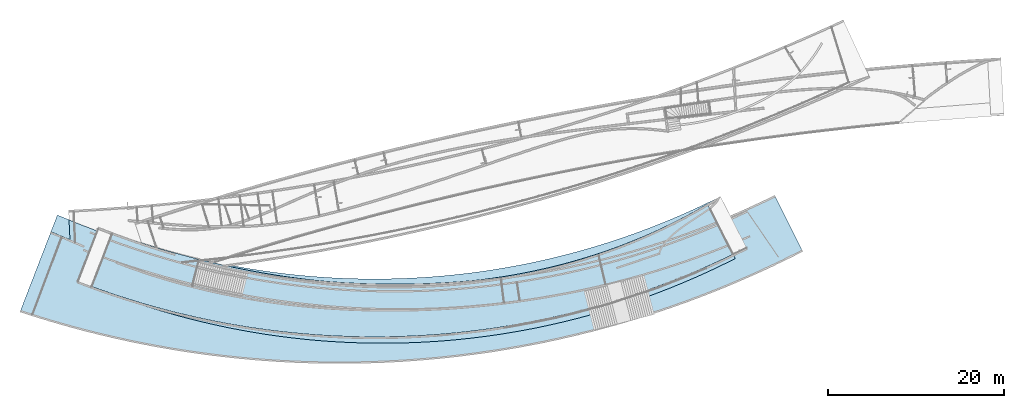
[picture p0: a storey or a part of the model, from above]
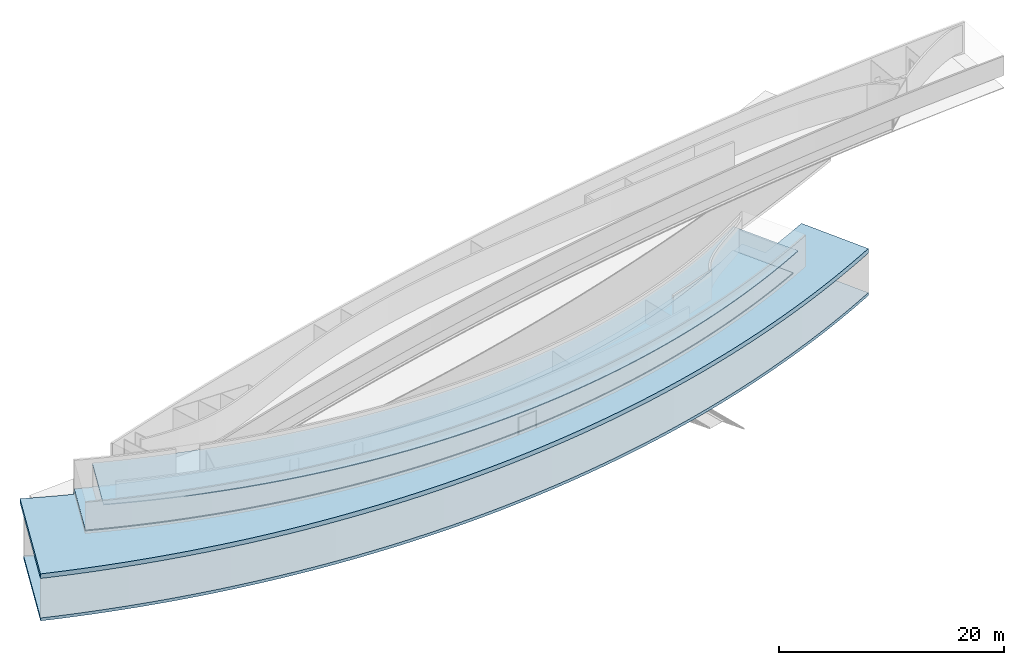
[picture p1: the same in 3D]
Properties of the parts of a building model (IFC2X3)

# File
Description: IFC 2x3 Building Model
Time: 2017-05-10T11:04:33
Organization: AppliCraft
Made in: ASIFC - 2.8.0.742

# IfcProject
LongName: ホキ美術館＿VisualARQ

# IfcSite, Site
RefLatitude: 47, 35, 59, 994506; RefLongitude: -122, -17, -59, -983520; RefElevation: 0 mm

# IfcCurtainWall: Single Panel (11)
In: Site
Type - PredefinedType: USERDEFINED

# IfcDoor: HOKI (2)
In: Site
Type - ParameterTakesPrecedence: yes; Sizeable: no
Type - IfcDoorLiningProperties - LiningDepth: 100 mm; LiningThickness: 50 mm
OverallHeight: 2000 mm; OverallWidth: 900 mm

# IfcDoor: HOKI entrance
In: Site
Type - OperationType: DOUBLE_DOOR_SLIDING; ParameterTakesPrecedence: yes; Sizeable: no
Type - IfcDoorPanelProperties - PanelDepth: 50 mm; PanelOperation: SLIDING; PanelWidth: 0.5; PanelPosition: LEFT
Type - IfcDoorLiningProperties - LiningDepth: 100 mm; LiningThickness: 50 mm
OverallHeight: 2000 mm; OverallWidth: 2000 mm

# IfcDoor: Hinged (4)
In: Site
Type - OperationType: SINGLE_SWING_LEFT; ParameterTakesPrecedence: yes; Sizeable: no
Type - IfcDoorPanelProperties - PanelDepth: 40 mm; PanelOperation: SWINGING; PanelWidth: 1; PanelPosition: LEFT
Type - IfcDoorLiningProperties - LiningThickness: 50 mm
OverallHeight: 2000 mm; OverallWidth: 700 mm

# IfcDoor: Hinged (7)
In: Site
Type - OperationType: SINGLE_SWING_RIGHT; ParameterTakesPrecedence: yes; Sizeable: no
Type - IfcDoorPanelProperties - PanelDepth: 40 mm; PanelOperation: SWINGING; PanelWidth: 1; PanelPosition: LEFT
Type - IfcDoorLiningProperties - LiningThickness: 50 mm
OverallHeight: 2000 mm; OverallWidth: 700 mm

# IfcDoor: Hinged Double
In: Site
Type - OperationType: DOUBLE_DOOR_SINGLE_SWING; ParameterTakesPrecedence: yes; Sizeable: no
Type - IfcDoorPanelProperties - PanelDepth: 40 mm; PanelOperation: SWINGING; PanelWidth: 0.5; PanelPosition: LEFT
Type - IfcDoorLiningProperties - LiningThickness: 50 mm
OverallHeight: 2000 mm; OverallWidth: 900 mm

# IfcProxy (17)
ProxyType: PRODUCT

# IfcSlab (6)
In: Site
PredefinedType: FLOOR
Name
3 x 
3 x edge

# IfcSlab: HOKI 1FA
In: Site
Type - PredefinedType: FLOOR; Material: Slab layer 1 250 mm
IfcElementQuantity - NominalWidth: 250 mm; NetArea: 599266641; NetVolume: 149816660356

# IfcSlab: HOKI 1FB (2)
In: Site
Type - PredefinedType: FLOOR; Material: Slab layer 1 320 mm
IfcElementQuantity - NominalWidth: 320 mm
Name | NetArea | NetVolume
 | 780296219 | 249694790103
 | 643890876 | 206045080277

# IfcSlab: HOKI 1FB UP
In: Site
Type - PredefinedType: FLOOR; Material: Slab layer 1 500 mm
IfcElementQuantity - NominalWidth: 500 mm; NetArea: 853101836; NetVolume: 426550918214

# IfcSlab: HOKI slab (7)
In: Site
Type - PredefinedType: FLOOR; Material: Slab layer 1 100 mm
IfcElementQuantity - NominalWidth: 100 mm
Name | NetArea | NetVolume
 | 447022108 | 44702210763
 | 472792223 | 47279222230
 | 597848540 | 59784854000
 | 637681244 | 63768124393
 | 468898843 | 46889884292
 | 660154206 | 66015420637
 | 652808793 | 65280879228

# IfcStair: Floating Balanced
In: Site
ShapeType: USERDEFINED
Pset_StairCommon - NumberOfRiser: 24; NumberOfTreads: 24; TreadLength: 250 mm; RiserHeight: 227.083 mm

# IfcStair: Plates (3)
In: Site
ShapeType: USERDEFINED
Pset_StairCommon - TreadLength: 250 mm
Name | NumberOfRiser = NumberOfTreads | RiserHeight (mm)
2 x  | 11 | 200
 | 23 | 232.609

# IfcWallStandardCase: HOKI 350 (26)
In: Site
Type - PredefinedType: STANDARD; Material: Wall layer 1 200 mm
Pset_WallCommon - ExtendToStructure: no
Name | NominalLength (mm) | NominalHeight (mm) | NetSideArea | NetVolume
 | 91441.7 | 4280 | 391370130 | 78274025875
 | 77648.1 | 4280 | 332334041 | 66466808166
 | 4129.49 | 4280 | 17674155 | 3534830952
 | 2649.92 | 4280 | 11449100 | 2289820084
 | 7950.68 | 4280 | 34440805 | 6888115881
 | 9247.93 | 3400 | 31441376 | 6288462896
 | 4734 | 4280 | 20539837 | 3827911633
 | 61719.7 | 3400 | 209021558 | 41770116064
 | 9272.27 | 3400 | 32289465 | 6459677757
 | 5181.53 | 3400 | 17423456 | 3484691222
 | 58548.1 | 2500 | 146370181 | 28545184055
 | 2238.26 | 2950 | 6995242 | 1403379452
 | 1145.96 | 2950 | 2701732 | 540344624
 | 8916.64 | 2950 | 25570963 | 5175555899
 | 76832.4 | 4280 | 328842734 | 65768546809
 | 62939.5 | 4500 | 282848051 | 56565142911
 | 19300.6 | 4500 | 86852652 | 17359722807
 | 70534.2 | 2950 | 208075823 | 41612013124
 | 21900.7 | 2950 | 64300806 | 12499557605
 | 12142.9 | 2950 | 36408594 | 7281568108
 | 64416.9 | 4280 | 275704416 | 55125613345
 | 76796.4 | 4280 | 328688554 | 65737710868
 | 91161.2 | 4280 | 390169071 | 77753672537
 | 78422.5 | 3400 | 266635842 | 45368775959
 | 100328 | 3400 | 341116713 | 68223342632
 | 91949 | 2100 | 193206610 | 38641260610

# IfcWallStandardCase: HOKI 50mm (34)
In: Site
Type - PredefinedType: STANDARD; Material: Wall layer 1 50 mm
Pset_WallCommon - ExtendToStructure: no
Name | NominalLength (mm) | NominalHeight (mm) | NetSideArea | NetVolume
 | 1116.4 | 400 | 467119 | 23355937
 | 3389.62 | 4280 | 14690665 | 734533332
 | 6366.25 | 250 | 1591516 | 79575784
 | 1298.87 | 650 | 844096 | 42204696
 | 3622.12 | 4280 | 15425361 | 771268011
 | 1298.85 | 4280 | 5747264 | 287363223
 | 5056.13 | 399.999 | 2012148 | 100607418
 | 5082.05 | 400 | 2022725 | 101134888
 | 1116.4 | 2950 | 3296453 | 164822612
 | 3198.13 | 4280 | 13511404 | 605568703
 | 2122.74 | 4280 | 7585386 | 379269602
 | 2315.65 | 4280 | 9248623 | 462431353
 | 1645.96 | 4280 | 7043274 | 282163759
 | 3264.76 | 4280 | 13964829 | 628241207
 | 3426.02 | 4280 | 14657115 | 662855406
 | 3541.2 | 4280 | 15158608 | 757929959
 | 3481.41 | 4280 | 14905906 | 745294887
 | 3333.15 | 4280 | 14275747 | 713786955
 | 3061.85 | 4280 | 13118452 | 655922282
 | 2764.03 | 2500 | 6490067 | 324503332
 | 3460.36 | 2500 | 8261583 | 413079151
 | 1765.05 | 2950 | 4645138 | 232256889
 | 2462.66 | 2950 | 6694061 | 334703037
 | 659.314 | 2950 | 0 | 1133445
 | 2377.55 | 2950 | 6260715 | 243036253
 | 3644.23 | 2950 | 10262789 | 443140010
 | 1834.25 | 2950 | 4928737 | 176436865
 | 1560.4 | 2950 | 4199699 | 139985097
 | 1696.43 | 2950 | 4838901 | 171945198
 | 633.608 | 2950 | 1393243 | 69662155
 | 7647.94 | 2950 | 22589403 | 1129470127
 | 2975.33 | 2950 | 8239108 | 411955417
 | 79107.4 | 3930 | 309326638 | 15466328423
 | 9216.39 | 4280 | 39514949 | 1975747257

# IfcWindow: Fixed (4)
In: Site
Type - OperationType: SINGLE_PANEL; ParameterTakesPrecedence: yes; Sizeable: no
Type - IfcWindowPanelProperties - OperationType: FIXEDCASEMENT; PanelPosition: LEFT
OverallHeight: 1500 mm; OverallWidth: 6000 mm
